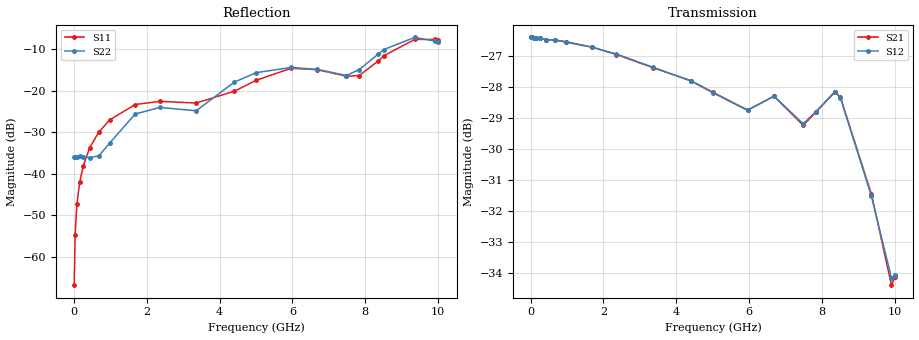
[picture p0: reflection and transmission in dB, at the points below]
! Device ID: PE43704
! Dir: z:\PE43704\PE43704_Char_1_20130516\PE43704\AMB\3p400V\25p50dB
! Serial: 14
! Insertion: A
! Impedance: 50 ohm
! Temp: Amb
! VDD: 3.400V
! Attenuation Step: 25.50dB
! IDD: 1.140390e-01mA
#  Hz  S  RI  R  50
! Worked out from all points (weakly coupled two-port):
!   401 points, 10 MHz to 10.01 GHz, reference 50 ohm
!   highest |S21| = -26.41 dB at 35 MHz (marker M1); lowest = -34.4 dB at 9.91 GHz (marker M2)
!   lowest |S11| = -66.9 dB at 10 MHz (marker M3), VSWR 1.00, Z = 50 + j0.0452 ohm
!   |S11| at or under -10 dB: start of sweep to 8.736 GHz
!   |S22| runs from -36.3 to -7.2 dB; largest |S21 - S12| = 0.00064
!   S11 on the Smith chart (normalised r, x): 10 MHz: 1.00, +0.00; 7.485 GHz: 0.78, +0.15; 8.51 GHz: 0.80, +0.45; 9.36 GHz: 0.54, +0.48; 10.01 GHz: 0.46, +0.27
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1e7  -4.39e-05 0.000452  0.0478 -0.000125  0.0478 -0.000112  0.0158 0.000232
3.5e7  0.000118 0.00182  0.0478 -0.000456  0.0478 -0.000445  0.0159 0.00109
8.5e7  2.62e-05 0.00431  0.0477 -0.00114  0.0477 -0.00107  0.0157 0.00278
1.6e8  -0.000365 0.00781  0.0477 -0.00203  0.0476 -0.00203  0.0152 0.00531
2.6e8  -0.00224 0.0122  0.0475 -0.00324  0.0475 -0.00321  0.0133 0.00847
4.35e8  -0.00659 0.0194  0.0471 -0.00531  0.0471 -0.00532  0.00847 0.0131
6.85e8  -0.0169 0.0266  0.0466 -0.0082  0.0466 -0.00822  -0.00182 0.0162
9.85e8  -0.0329 0.0298  0.0456 -0.0115  0.0455 -0.0115  -0.0181 0.0148
1.685e9  -0.0662 0.0151  0.0421 -0.0188  0.0421 -0.0188  -0.0515 -0.00831
2.36e9  -0.074 -0.004  0.0375 -0.0246  0.0376 -0.0246  -0.0572 -0.0253
3.36e9  -0.0707 -0.000865  0.0294 -0.031  0.0294 -0.0311  -0.057 -0.00359
4.41e9  -0.0883 0.0434  0.0211 -0.0348  0.021 -0.0348  -0.1151 0.0531
5.01e9  -0.112 0.0717  0.017 -0.0351  0.0168 -0.0351  -0.1504 0.0661
5.96e9  -0.1595 0.0945  0.00971 -0.0352  0.00988 -0.0351  -0.1729 0.078
6.685e9  -0.1593 0.0799  0.00579 -0.038  0.00583 -0.038  -0.1572 0.0876
7.485e9  -0.1155 0.0934  0.000324 -0.0345  0.000282 -0.0347  -0.0814 0.128
7.835e9  -0.0724 0.1333  -0.000587 -0.0362  -0.000548 -0.0363  -0.0602 0.1688
8.36e9  -0.041 0.2238  -0.00986 -0.0378  -0.00964 -0.0379  -0.066 0.267
8.51e9  -0.0443 0.2583  -0.0127 -0.0361  -0.0124 -0.0361  -0.075 0.3027
9.36e9  -0.1875 0.3681  -0.016 -0.0214  -0.0158 -0.0213  -0.2071 0.3843
9.91e9  -0.3067 0.2757  -0.00631 -0.018  -0.00668 -0.0184  -0.301 0.2532
1.001e10  -0.3241 0.2415  -0.00431 -0.0192  -0.00478 -0.0192  -0.3117 0.2163
